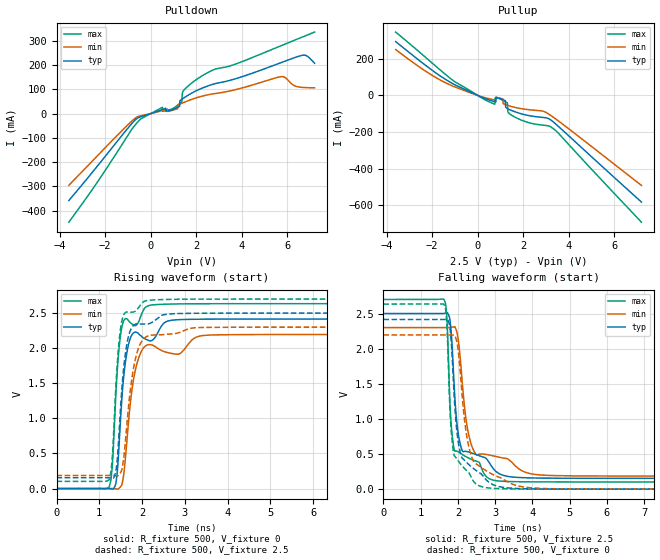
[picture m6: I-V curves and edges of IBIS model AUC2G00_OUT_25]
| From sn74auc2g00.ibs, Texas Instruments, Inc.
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[Model]   AUC2G00_OUT_25
Model_type  Output
Vref =   0
Rref =   500
Cref =   30p
Vmeas =   1.25
| variable   typ   min   max
C_comp   7.45pF   0.27pF   23.62pF
| C_pullup   8.36pF   0.27pF   23.62pF
| C_pulldown   6.53pF   1.89pF   15.75pF
[Temperature Range]   40   100   -40
| Ambient temperature   25   85   -40
[Voltage range]   2.5   2.3   2.7
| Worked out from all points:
|   slope of the pulldown table from 0 to 0.375 V, typ, clamps not added: 30.9 ohm
|   slope of the pullup table from 0 to 0.375 V, typ, clamps not added: 19.2 ohm
|   rising waveform, R_fixture 500, V_fixture 0: 20-80 % time 195ps typ, 258ps min, 157ps max; typ from 0 V to 2.42 V
|   falling waveform, R_fixture 500, V_fixture 2.5: 20-80 % time 226ps typ, 316ps min, 156ps max; typ from 2.5 V to 0.154 V
|   rising waveform, R_fixture 500, V_fixture 2.5: 20-80 % time 192ps typ, 257ps min, 155ps max; typ from 0.154 V to 2.5 V
|   falling waveform, R_fixture 500, V_fixture 0: 20-80 % time 241ps typ, 337ps min, 159ps max; typ from 2.42 V to 0 V
[Pulldown]
| AUC2G00_OUT_25
|   Voltage   I(typ)   I(min)   I(max)
-3.6V     -357.9mA   -295mA     -446.9mA
-445mV    -13.39mA   -9.086mA   -23.04mA
515mV     17.02mA    12.57mA    25.99mA
1.03V     19.04mA    15.49mA    23.85mA
1.27V     29.99mA    38.36mA    41.3mA
1.37V     59.29mA    42.41mA    48.87mA
1.395V    60.81mA    43.42mA    85.06mA
1.48V     65.92mA    46.77mA    98.72mA
2.545V    114.8mA    77.91mA    170.6mA
5.695V    208.4mA    151.5mA    277.8mA
6.74V     240.4mA    107.1mA    317.8mA
7.2V      207mA      105.9mA    335.2mA
[Pullup]
| AUC2G00_OUT_25
|   Voltage   I(typ)   I(min)   I(max)
-3.6V     293.6mA    250.5mA    345.5mA
-960mV    55.5mA     44.14mA    71.53mA
730mV     -33.82mA   -24.42mA   -47.21mA
760mV     -34.84mA   -25.13mA   -47.16mA
770mV     -35.18mA   -25.36mA   -13.07mA
1.115V    -23.84mA   -20.26mA   -27.67mA
1.215V    -28.81mA   -50.48mA   -34.67mA
1.295V    -71.05mA   -53.78mA   -40.2mA
1.345V    -74.3mA    -55.73mA   -93.3mA
1.755V    -94.43mA   -68.81mA   -126mA
3.31V     -143.6mA   -118mA     -180.4mA
7.2V      -582.7mA   -491.8mA   -692.5mA
[Ramp]
| AUC2G00_OUT_25
| variable   typ   min   max
dV/dt_r   1.45/1.97E-10   1.32/2.59E-10   1.58/1.58E-10
dV/dt_f   1.41/2.27E-10   1.28/3.18E-10   1.56/1.58E-10
R_load = 500
[Rising Waveform]
| AUC2G00_OUT_25
R_fixture =   500
C_fixture =   0
L_fixture =   0
V_fixture =   0
V_fixture_min = 0
V_fixture_max = 0
|   Time   V(typ)   V(min)   V(max)
0s        9.791nV    28.67nV    1.858nV
1.23ns    -1.161mV   381.6uV    19.94mV
1.305ns   -6.43mV    211.1uV    333.5mV
1.395ns   105.1mV    -4.992mV   1.436V
1.53ns    1.304V     60.53mV    2.309V
1.66ns    1.987V     788.2mV    2.409V
1.825ns   2.227V     1.637V     2.321V
2.18ns    2.104V     2.051V     2.611V
2.975ns   2.409V     1.973V     2.632V
21.47ns   2.416V     2.195V     2.634V
[Falling Waveform]
| AUC2G00_OUT_25
R_fixture =   500
C_fixture =   0
L_fixture =   0
V_fixture =   2.5
V_fixture_min = 2.3
V_fixture_max = 2.7
|   Time   V(typ)   V(min)   V(max)
0s        2.5V       2.3V       2.7V
1.625ns   2.501V     2.3V       2.702V
1.705ns   2.509V     2.3V       2.428V
1.785ns   2.416V     2.302V     1.261V
1.905ns   1.433V     2.312V     557.2mV
2.075ns   618.4mV    1.796V     509.1mV
2.35ns    519.1mV    652.4mV    427.7mV
2.96ns    285.8mV    472.4mV    127mV
4.555ns   156.2mV    193.6mV    103.1mV
21.47ns   154.5mV    186.3mV    102.6mV
[Rising Waveform]
| AUC2G00_OUT_25
R_fixture =   500
C_fixture =   0
L_fixture =   0
V_fixture =   2.5
V_fixture_min = 2.3
V_fixture_max = 2.7
|   Time   V(typ)   V(min)   V(max)
0s        154.5mV    186.3mV    102.6mV
1.23ns    153.4mV    186.5mV    124.4mV
1.305ns   149.8mV    186.4mV    457.5mV
1.39ns    257.5mV    182.6mV    1.484V
1.525ns   1.406V     260.8mV    2.381V
1.65ns    2.076V     949mV      2.515V
1.8ns     2.326V     1.715V     2.515V
2.09ns    2.345V     2.159V     2.676V
3.11ns    2.497V     2.28V      2.699V
21.47ns   2.5V       2.3V       2.7V
[Falling Waveform]
| AUC2G00_OUT_25
R_fixture =   500
C_fixture =   0
L_fixture =   0
V_fixture =   0
V_fixture_min = 0
V_fixture_max = 0
|   Time   V(typ)   V(min)   V(max)
0s        2.416V     2.195V     2.634V
1.62ns    2.415V     2.195V     2.636V
1.705ns   2.418V     2.195V     2.331V
1.78ns    2.33V      2.195V     1.221V
1.89ns    1.433V     2.192V     501.9mV
2.085ns   477.9mV    1.527V     349.7mV
2.315ns   340.1mV    555.7mV    215.9mV
2.68ns    184.5mV    290mV      29.04mV
4.4ns     1.891mV    7.872mV    502.9uV
21.47ns   20.93uV    2.802uV    10.34uV
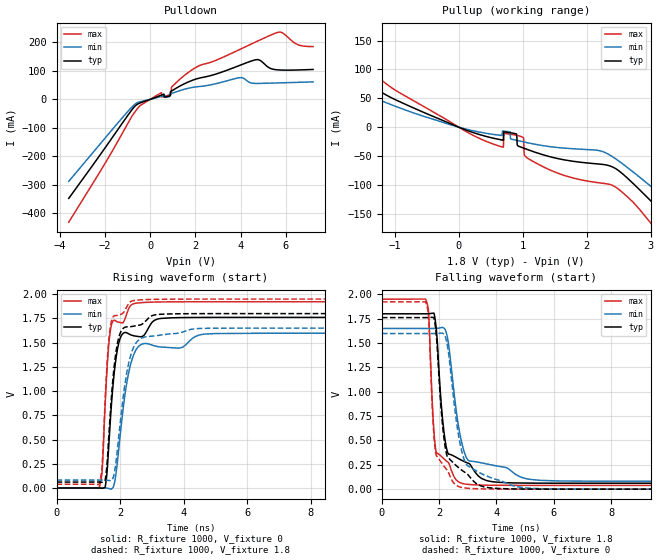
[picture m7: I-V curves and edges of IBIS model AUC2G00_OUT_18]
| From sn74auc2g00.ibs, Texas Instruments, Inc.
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[Model]   AUC2G00_OUT_18
Model_type  Output
Vref =   0
Rref =   1000
Cref =   30p
Vmeas =   0.9
| variable   typ   min   max
C_comp   6.69pF   0.25pF   21.38pF
| C_pullup   7.14pF   1.04pF   21.38pF
| C_pulldown   6.24pF   0.25pF   15.43pF
[Temperature Range]   40   100   -40
| Ambient temperature   25   85   -40
[Voltage range]   1.8   1.65   1.95
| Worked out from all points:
|   slope of the pulldown table from 0 to 0.27 V, typ, clamps not added: 34.4 ohm
|   slope of the pullup table from 0 to 0.27 V, typ, clamps not added: 24.7 ohm
|   rising waveform, R_fixture 1000, V_fixture 0: 20-80 % time 277ps typ, 401ps min, 193ps max; typ from 0 V to 1.76 V
|   falling waveform, R_fixture 1000, V_fixture 1.8: 20-80 % time 318ps typ, 471ps min, 204ps max; typ from 1.8 V to 0.061 V
|   rising waveform, R_fixture 1000, V_fixture 1.8: 20-80 % time 273ps typ, 392ps min, 191ps max; typ from 0.061 V to 1.8 V
|   falling waveform, R_fixture 1000, V_fixture 0: 20-80 % time 324ps typ, 480ps min, 204ps max; typ from 1.76 V to 0 V
[Pulldown]
| AUC2G00_OUT_18
|   Voltage   I(typ)   I(min)   I(max)
-3.6V     -347.6mA   -287.8mA   -431.2mA
-830mV    -38.94mA   -28.94mA   -62.22mA
-405mV    -11.33mA   -7.446mA   -19.55mA
495mV     14.95mA    10.62mA    23.51mA
885mV     12.26mA    19.06mA    15.87mA
925mV     28.54mA    20.16mA    16.88mA
960mV     30.1mA     21.15mA    44.31mA
2.045V    71.87mA    43.99mA    113.3mA
3.92V     118.2mA    75.85mA    173.7mA
4.625V    138.4mA    55.98mA    200.1mA
5.58V     103.9mA    57.6mA     233.8mA
7.2V      105mA      61.31mA    185.3mA
[Pullup]
| AUC2G00_OUT_18
|   Voltage   I(typ)   I(min)   I(max)
-3.6V     267.6mA    221.5mA    318.7mA
-2.61V    174.3mA    138.3mA    219.8mA
-2.13V    131.5mA    101.8mA    171.7mA
110mV     -4.812mA   -3.244mA   -7.318mA
695mV     -22.64mA   -6.826mA   -34.84mA
705mV     -8.168mA   -6.941mA   -10.57mA
980mV     -34.9mA    -24.66mA   -16.5mA
1.11V     -40.21mA   -27.81mA   -56.13mA
2.25V     -64.62mA   -42.31mA   -97.29mA
3.1V      -138.6mA   -111.4mA   -179.7mA
3.915V    -230.4mA   -188mA     -289.7mA
7.2V      -598mA     -503.3mA   -721.1mA
[Ramp]
| AUC2G00_OUT_18
| variable   typ   min   max
dV/dt_r   1.06/2.79E-10   0.97/4.03E-10   1.16/1.93E-10
dV/dt_f   1.05/3.20E-10   0.95/4.76E-10   1.15/2.09E-10
R_load = 1000
[Rising Waveform]
| AUC2G00_OUT_18
R_fixture =   1000
C_fixture =   0
L_fixture =   0
V_fixture =   0
V_fixture_min = 0
V_fixture_max = 0
|   Time   V(typ)   V(min)   V(max)
0s        7.669nV    26.14nV    1.117nV
1.335ns   413.6uV    370.9uV    -1.662mV
1.43ns    -3.344mV   625.4uV    146.9mV
1.545ns   37.2mV     269.6uV    961.4mV
1.71ns    775mV      -11.33mV   1.654V
1.985ns   1.527V     485.5mV    1.709V
2.21ns    1.602V     1.083V     1.797V
2.455ns   1.569V     1.396V     1.904V
3.62ns    1.757V     1.448V     1.921V
22.04ns   1.761V     1.597V     1.922V
[Falling Waveform]
| AUC2G00_OUT_18
R_fixture =   1000
C_fixture =   0
L_fixture =   0
V_fixture =   1.8
V_fixture_min = 1.65
V_fixture_max = 1.95
|   Time   V(typ)   V(min)   V(max)
0s        1.8V       1.65V      1.95V
1.54ns    1.8V       1.65V      1.943V
1.625ns   1.8V       1.65V      1.839V
1.78ns    1.806V     1.65V      775.4mV
1.89ns    1.671V     1.65V      389.8mV
2.085ns   831.3mV    1.659V     334mV
2.245ns   437mV      1.611V     291.3mV
2.81ns    292.7mV    450mV      58.65mV
5.5ns     61.77mV    90.98mV    38.82mV
22.04ns   61.07mV    81.21mV    38.69mV
[Rising Waveform]
| AUC2G00_OUT_18
R_fixture =   1000
C_fixture =   0
L_fixture =   0
V_fixture =   1.8
V_fixture_min = 1.65
V_fixture_max = 1.95
|   Time   V(typ)   V(min)   V(max)
0s        61.05mV    81.2mV     38.68mV
1.335ns   61.41mV    81.51mV    37.46mV
1.43ns    58.04mV    81.7mV     195.3mV
1.535ns   89.78mV    81.57mV    938.5mV
1.705ns   835mV      75.54mV    1.685V
1.96ns    1.555V     537.1mV    1.786V
2.18ns    1.661V     1.129V     1.851V
2.4ns     1.669V     1.432V     1.932V
4.525ns   1.8V       1.647V     1.95V
22.04ns   1.8V       1.65V      1.95V
[Falling Waveform]
| AUC2G00_OUT_18
R_fixture =   1000
C_fixture =   0
L_fixture =   0
V_fixture =   0
V_fixture_min = 0
V_fixture_max = 0
|   Time   V(typ)   V(min)   V(max)
0s        1.761V     1.597V     1.922V
1.535ns   1.761V     1.597V     1.917V
1.625ns   1.761V     1.597V     1.803V
1.775ns   1.763V     1.597V     759.5mV
1.88ns    1.64V      1.597V     368.5mV
2.225ns   408.1mV    1.558V     214.4mV
2.72ns    210.8mV    483.2mV    22.79mV
2.99ns    153.2mV    242.4mV    9.503mV
5.045ns   1.135mV    12.32mV    204.5uV
22.04ns   24.49uV    3.295uV    10.71uV
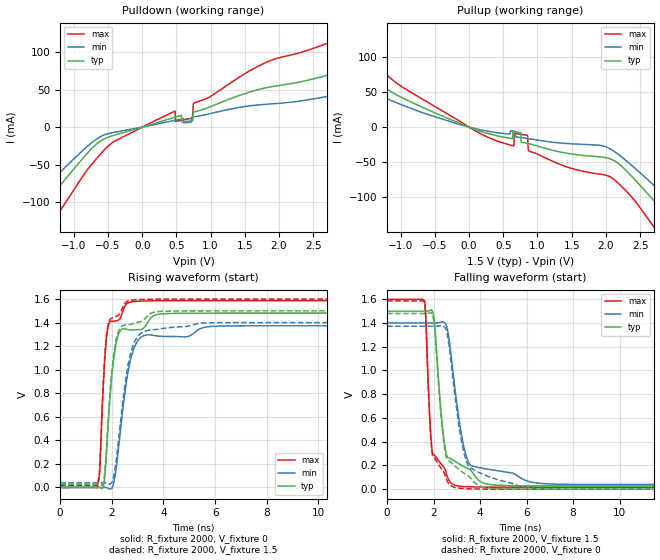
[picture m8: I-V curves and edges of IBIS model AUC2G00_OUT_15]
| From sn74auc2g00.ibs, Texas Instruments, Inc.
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[Model]   AUC2G00_OUT_15
Model_type  Output
Vref =   0
Rref =   2000
Cref =   15p
Vmeas =   0.75
| variable   typ   min   max
C_comp   6.42pF   1.69pF   19.05pF
| C_pullup   6.13pF   1.69pF   19.05pF
| C_pulldown   6.70pF   3.60pF   15.20pF
[Temperature Range]   40   100   -40
| Ambient temperature   25   85   -40
[Voltage range]   1.5   1.4   1.6
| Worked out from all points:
|   slope of the pulldown table from 0 to 0.225 V, typ, clamps not added: 36.6 ohm
|   slope of the pullup table from 0 to 0.225 V, typ, clamps not added: 29.5 ohm
|   rising waveform, R_fixture 2000, V_fixture 0: 20-80 % time 342ps typ, 509ps min, 226ps max; typ from 0 V to 1.48 V
|   falling waveform, R_fixture 2000, V_fixture 1.5: 20-80 % time 406ps typ, 605ps min, 235ps max; typ from 1.5 V to 0.027 V
|   rising waveform, R_fixture 2000, V_fixture 1.5: 20-80 % time 336ps typ, 502ps min, 224ps max; typ from 0.027 V to 1.5 V
|   falling waveform, R_fixture 2000, V_fixture 0: 20-80 % time 408ps typ, 612ps min, 234ps max; typ from 1.48 V to 0 V
[Pulldown]
| AUC2G00_OUT_15
|   Voltage   I(typ)   I(min)   I(max)
-3.6V     -343mA     -284.8mA   -423.7mA
-2.105V   -179.1mA   -144.1mA   -232.4mA
-1.795V   -144.7mA   -115.1mA   -192.1mA
-1.395V   -99.88mA   -78mA      -138.7mA
-395mV    -10.45mA   -6.753mA   -18.28mA
480mV     13.33mA    9.224mA    21.44mA
485mV     13.46mA    9.315mA    7.619mA
735mV     8.724mA    13.39mA    12.06mA
755mV     20.22mA    13.69mA    32.02mA
1.69V     50.03mA    29.61mA    81.13mA
3.34V     86.07mA    49.98mA    134.3mA
7.2V      80.6mA     45.5mA     141.2mA
[Pullup]
| AUC2G00_OUT_15
|   Voltage   I(typ)   I(min)   I(max)
-3.6V     254.2mA    195.1mA    304.8mA
-2.875V   187.5mA    148mA      233.8mA
-2.45V    149.7mA    116.2mA    192.1mA
-1.91V    104.4mA    79.22mA    139.6mA
100mV     -3.652mA   -2.395mA   -5.808mA
650mV     -6.722mA   -5.654mA   -26.6mA
855mV     -23.22mA   -16.17mA   -11.7mA
885mV     -23.88mA   -16.62mA   -34.51mA
2.105V    -46.97mA   -33.55mA   -73.62mA
2.76V     -111.3mA   -88.18mA   -150.1mA
3.36V     -178.2mA   -143.6mA   -230.9mA
7.2V      -605.9mA   -510.3mA   -734mA
[Ramp]
| AUC2G00_OUT_15
| variable   typ   min   max
dV/dt_r   0.89/3.44E-10   0.83/5.15E-10   0.95/2.27E-10
dV/dt_f   0.89/4.07E-10   0.82/6.08E-10   0.95/2.44E-10
R_load = 2000
[Rising Waveform]
| AUC2G00_OUT_15
R_fixture =   2000
C_fixture =   0
L_fixture =   0
V_fixture =   0
V_fixture_min = 0
V_fixture_max = 0
|   Time   V(typ)   V(min)   V(max)
0s        7.042nV    26.32nV    876.9pV
1.43ns    519.8uV    333.3uV    -3.88mV
1.53ns    -1.276mV   511.6uV    132.3mV
1.695ns   28.68mV    721.1uV    966.6mV
1.84ns    460.8mV    -4.356mV   1.347V
2.175ns   1.231V     172.7mV    1.416V
2.675ns   1.339V     1.035V     1.571V
3.21ns    1.349V     1.286V     1.583V
5.81ns    1.48V      1.367V     1.587V
22.06ns   1.481V     1.373V     1.587V
[Falling Waveform]
| AUC2G00_OUT_15
R_fixture =   2000
C_fixture =   0
L_fixture =   0
V_fixture =   1.5
V_fixture_min = 1.4
V_fixture_max = 1.6
|   Time   V(typ)   V(min)   V(max)
0s        1.5V       1.4V       1.6V
1.625ns   1.5V       1.4V       1.583V
1.83ns    1.505V     1.4V       636.4mV
1.95ns    1.498V     1.4V       311.2mV
2.485ns   365mV      1.402V     171.2mV
2.915ns   235.7mV    857.7mV    33.55mV
3.255ns   195.9mV    401mV      22.76mV
3.57ns    165.7mV    206.2mV    19.58mV
6.205ns   27.73mV    59.5mV     16.5mV
22.06ns   27.2mV     38.79mV    16.41mV
[Rising Waveform]
| AUC2G00_OUT_15
R_fixture =   2000
C_fixture =   0
L_fixture =   0
V_fixture =   1.5
V_fixture_min = 1.4
V_fixture_max = 1.6
|   Time   V(typ)   V(min)   V(max)
0s        27.17mV    38.78mV    16.4mV
1.43ns    27.65mV    39.07mV    12.68mV
1.53ns    25.96mV    39.22mV    155.6mV
1.69ns    59.47mV    39.35mV    973.6mV
1.83ns    471.3mV    35.63mV    1.354V
2.15ns    1.236V     198.6mV    1.451V
2.625ns   1.381V     1.036V     1.584V
3.195ns   1.417V     1.318V     1.597V
5.47ns    1.5V       1.396V     1.6V
22.06ns   1.5V       1.4V       1.6V
[Falling Waveform]
| AUC2G00_OUT_15
R_fixture =   2000
C_fixture =   0
L_fixture =   0
V_fixture =   0
V_fixture_min = 0
V_fixture_max = 0
|   Time   V(typ)   V(min)   V(max)
0s        1.481V     1.373V     1.587V
1.625ns   1.48V      1.373V     1.568V
1.83ns    1.485V     1.373V     610.9mV
1.945ns   1.477V     1.372V     299.2mV
2.465ns   357.5mV    1.37V      132.7mV
2.865ns   204.4mV    879.6mV    17.26mV
3.205ns   148.9mV    402.3mV    6.494mV
3.51ns    109.5mV    193.3mV    3.32mV
5.785ns   771.2uV    21.4mV     120.3uV
22.06ns   29.25uV    5.444uV    11.79uV
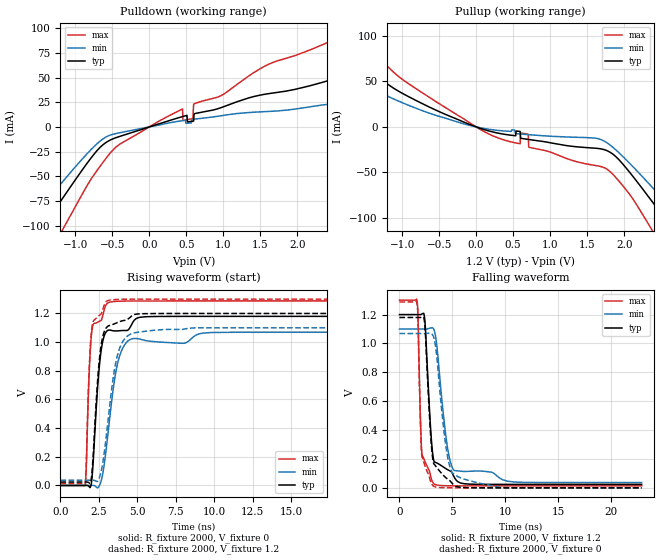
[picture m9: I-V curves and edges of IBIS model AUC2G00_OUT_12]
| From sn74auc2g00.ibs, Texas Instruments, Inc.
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[Model]   AUC2G00_OUT_12
Model_type  Output
Vref =   0
Rref =   2000
Cref =   15p
Vmeas =   0.6
| variable   typ   min   max
C_comp   5.93pF   2.37pF   15.74pF
| C_pullup   5.52pF   2.37pF   15.74pF
| C_pulldown   6.35pF   4.16pF   14.94pF
[Temperature Range]   40   100   -40
| Ambient temperature   25   85   -40
[Voltage range]   1.2   1.1   1.3
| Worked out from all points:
|   slope of the pulldown table from 0 to 0.18 V, typ, clamps not added: 42.3 ohm
|   slope of the pullup table from 0 to 0.18 V, typ, clamps not added: 38.7 ohm
|   rising waveform, R_fixture 2000, V_fixture 0: 20-80 % time 482ps typ, 795ps min, 284ps max; typ from 0 V to 1.18 V
|   falling waveform, R_fixture 2000, V_fixture 1.2: 20-80 % time 560ps typ, 947ps min, 290ps max; typ from 1.2 V to 0.024 V
|   rising waveform, R_fixture 2000, V_fixture 1.2: 20-80 % time 474ps typ, 785ps min, 278ps max; typ from 0.024 V to 1.2 V
|   falling waveform, R_fixture 2000, V_fixture 0: 20-80 % time 558ps typ, 955ps min, 287ps max; typ from 1.18 V to 0 V
[Pulldown]
| AUC2G00_OUT_12
|   Voltage   I(typ)   I(min)   I(max)
-3.6V     -338.3mA   -281.2mA   -417.3mA
-1.81V    -142.4mA   -113.5mA   -188.2mA
-1.485V   -106.7mA   -83.68mA   -145.8mA
-1.225V   -78.14mA   -60.24mA   -111.4mA
-715mV    -24.74mA   -17.64mA   -45.05mA
-390mV    -9.376mA   -5.759mA   -17.06mA
450mV     10.5mA     6.398mA    18.24mA
590mV     5.848mA    7.731mA    8.546mA
605mV     12.96mA    7.861mA    23.36mA
2.86V     55.94mA    19.09mA    100.7mA
3.425V    44.57mA    20.08mA    119.3mA
7.2V      57.06mA    26.82mA    108mA
[Pullup]
| AUC2G00_OUT_12
|   Voltage   I(typ)   I(min)   I(max)
-3.6V     224.6mA    100.8mA    291.5mA
-2.7V     158.6mA    66.17mA    205.2mA
-2.11V    110.3mA    77.88mA    148.7mA
-1.68V    77.88mA    55.75mA    108.7mA
-1.025V   38.18mA    27.56mA    53.97mA
50mV      -1.427mA   -842.9uA   -2.489mA
700mV     -13.68mA   -8.451mA   -7.891mA
1.78V     -26.5mA    -18.1mA    -47.09mA
2.4V      -84.34mA   -68.12mA   -116.4mA
2.695V    -116.7mA   -94.74mA   -156.1mA
3.045V    -155.5mA   -127mA     -202.8mA
7.2V      -615.6mA   -521.5mA   -745mA
[Ramp]
| AUC2G00_OUT_12
| variable   typ   min   max
dV/dt_r   0.72/4.91E-10   0.65/8.04E-10   0.77/2.86E-10
dV/dt_f   0.71/5.65E-10   0.64/9.53E-10   0.78/2.98E-10
R_load = 2000
[Rising Waveform]
| AUC2G00_OUT_12
R_fixture =   2000
C_fixture =   0
L_fixture =   0
V_fixture =   0
V_fixture_min = 0
V_fixture_max = 0
|   Time   V(typ)   V(min)   V(max)
0s        6.587nV    27.93nV    705.3pV
1.625ns   446.8uV    213.2uV    3.711mV
1.84ns    -4.255mV   499.1uV    700.9mV
1.97ns    -4.138mV   747.2uV    989.2mV
2.135ns   171.6mV    701uV      1.123V
2.58ns    882.7mV    10.28mV    1.148V
3.11ns    1.084V     377.6mV    1.275V
3.75ns    1.079V     865.8mV    1.285V
4.615ns   1.119V     1.022V     1.287V
22.92ns   1.18V      1.069V     1.287V
[Falling Waveform]
| AUC2G00_OUT_12
R_fixture =   2000
C_fixture =   0
L_fixture =   0
V_fixture =   1.2
V_fixture_min = 1.1
V_fixture_max = 1.3
|   Time   V(typ)   V(min)   V(max)
0s        1.2V       1.1V       1.3V
1.66ns    1.2V       1.1V       1.295V
1.75ns    1.2V       1.1V       1.198V
2.07ns    1.202V     1.1V       303.3mV
2.32ns    1.204V     1.099V     200.4mV
2.985ns   373.3mV    1.107V     70.99mV
3.29ns    181.2mV    1.092V     26.82mV
4.48ns    129.2mV    312.9mV    14.7mV
5.17ns    76.42mV    121.3mV    14.16mV
22.92ns   24.01mV    36.66mV    13.87mV
[Rising Waveform]
| AUC2G00_OUT_12
R_fixture =   2000
C_fixture =   0
L_fixture =   0
V_fixture =   1.2
V_fixture_min = 1.1
V_fixture_max = 1.3
|   Time   V(typ)   V(min)   V(max)
0s        23.98mV    36.64mV    13.86mV
1.625ns   24.35mV    36.82mV    21.51mV
1.835ns   20.76mV    37mV       714.5mV
1.955ns   22.5mV     37.12mV    990.3mV
2.115ns   184.9mV    37.15mV    1.139V
2.55ns    894.1mV    60.87mV    1.188V
3.03ns    1.106V     388.9mV    1.287V
3.705ns   1.136V     906.6mV    1.298V
4.68ns    1.186V     1.061V     1.3V
22.92ns   1.2V       1.1V       1.3V
[Falling Waveform]
| AUC2G00_OUT_12
R_fixture =   2000
C_fixture =   0
L_fixture =   0
V_fixture =   0
V_fixture_min = 0
V_fixture_max = 0
|   Time   V(typ)   V(min)   V(max)
0s        1.18V      1.069V     1.287V
1.655ns   1.18V      1.069V     1.282V
1.75ns    1.18V      1.069V     1.177V
2.06ns    1.181V     1.069V     295.7mV
2.31ns    1.179V     1.069V     178mV
2.945ns   373.5mV    1.069V     45.97mV
3.205ns   178.4mV    1.05V      13.46mV
4.42ns    68.74mV    276.4mV    819.4uV
5.105ns   22.67mV    97.94mV    293.4uV
22.92ns   32.57uV    9.226uV    12.49uV
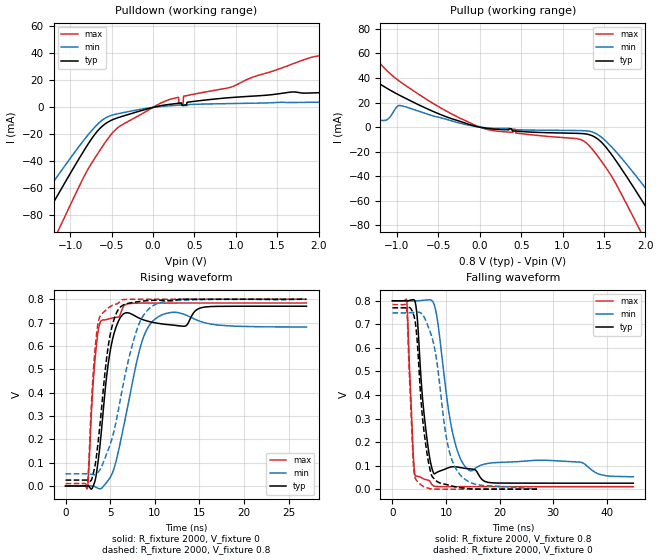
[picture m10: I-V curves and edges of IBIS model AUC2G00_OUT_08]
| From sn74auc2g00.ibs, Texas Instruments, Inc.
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[Model]   AUC2G00_OUT_08
Model_type  Output
Vref =   0
Rref =   2000
Cref =   15p
Vmeas =   0.4
| variable   typ   min   max
C_comp   5.67pF   2.72pF   7.64pF
| C_pullup   5.14pF   2.72pF   7.64pF
| C_pulldown   6.20pF   5.44pF   6.81pF
[Temperature Range]   40   100   -40
| Ambient temperature   25   85   -40
[Voltage range]   0.8   0.8   0.8
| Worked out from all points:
|   slope of the pulldown table from 0 to 0.12 V, typ, clamps not added: 77.1 ohm
|   slope of the pullup table from 0 to 0.12 V, typ, clamps not added: 92.8 ohm
|   rising waveform, R_fixture 2000, V_fixture 0: 20-80 % time 1.39ns typ, 2.21ns min, 814ps max; typ from 0 V to 0.77 V
|   falling waveform, R_fixture 2000, V_fixture 0.8: 20-80 % time 1.76ns typ, 2.84ns min, 866ps max; typ from 0.8 V to 0.026 V
|   rising waveform, R_fixture 2000, V_fixture 0.8: 20-80 % time 1.37ns typ, 2.64ns min, 761ps max; typ from 0.025 V to 0.8 V
|   falling waveform, R_fixture 2000, V_fixture 0: 20-80 % time 1.78ns typ, 2.87ns min, 865ps max; typ from 0.77 V to 0 V
[Pulldown]
| AUC2G00_OUT_08
|   Voltage   I(typ)   I(min)   I(max)
-3.6V     -332mA     -277.5mA   -406.5mA
-1.635V   -117.5mA   -94.15mA   -155.2mA
-1.375V   -89.26mA   -70.66mA   -121.5mA
-1.155V   -65.6mA    -51.21mA   -92.88mA
-630mV    -14.96mA   -10.34mA   -30.86mA
-430mV    -7.788mA   -4.786mA   -15.33mA
-90mV     -1.494mA   -794.3uA   -3.292mA
210mV     2.329mA    1.254mA    6.027mA
365mV     1.692mA    1.285mA    2.781mA
1.98V     10.83mA    3.867mA    38.03mA
2.365V    11.74mA    4.199mA    33.49mA
7.2V      23.85mA    8.894mA    59.33mA
[Pullup]
| AUC2G00_OUT_08
|   Voltage   I(typ)   I(min)   I(max)
-3.6V     79.74mA    9.11mA     185.5mA
-3.08V    78.24mA    9.441mA    162.7mA
-1.59V    27.55mA    11.02mA    82.8mA
-1.305V   38.33mA    6.645mA    59.6mA
-1.13V    31.97mA    5.759mA    46.58mA
-975mV    26.17mA    17.62mA    37.64mA
-245mV    4.854mA    3.296mA    7.479mA
1.36V     -7.061mA   -3.966mA   -18.08mA
1.875V    -50.9mA    -38.75mA   -76.11mA
2.115V    -76.5mA    -59.54mA   -107.8mA
2.405V    -108mA     -85.49mA   -146mA
7.2V      -633.7mA   -537.1mA   -765.1mA
[Ramp]
| AUC2G00_OUT_08
| variable   typ   min   max
dV/dt_r   0.47/1.41E-09   0.45/2.50E-09   0.48/8.20E-10
dV/dt_f   0.47/1.76E-09   0.45/2.84E-09   0.48/8.72E-10
R_load = 2000
[Rising Waveform]
| AUC2G00_OUT_08
R_fixture =   2000
C_fixture =   0
L_fixture =   0
V_fixture =   0
V_fixture_min = 0
V_fixture_max = 0
|   Time   V(typ)   V(min)   V(max)
0s        8.079nV    45.62nV    527.9pV
2.445ns   704.3uV    733.6uV    -7.839mV
3.255ns   16.1mV     -2.427mV   521.8mV
3.655ns   108.7mV    -9.825mV   665.4mV
4.025ns   240.2mV    -9.757mV   709.3mV
4.92ns    559.9mV    32.03mV    716.5mV
5.985ns   711mV      160.5mV    724.8mV
8.38ns    716.7mV    595.3mV    783.3mV
10.06ns   698.7mV    716.2mV    783.6mV
27ns      770mV      681mV      783.7mV
[Falling Waveform]
| AUC2G00_OUT_08
R_fixture =   2000
C_fixture =   0
L_fixture =   0
V_fixture =   0.8
V_fixture_min = 0.8
V_fixture_max = 0.8
|   Time   V(typ)   V(min)   V(max)
0s        800mV      800mV      800mV
2.66ns    799.1mV    799.8mV    801.1mV
3.87ns    804.8mV    799.4mV    156.6mV
4.29ns    790.2mV    799.4mV    55.11mV
5.975ns   304.7mV    802.7mV    42.26mV
7.77ns    65.54mV    784.9mV    13.01mV
11.1ns    94.86mV    253.6mV    10.67mV
14.07ns   87.05mV    84.78mV    10.64mV
28.86ns   25.55mV    122.6mV    10.61mV
45ns      25.5mV     52.61mV    10.6mV
[Rising Waveform]
| AUC2G00_OUT_08
R_fixture =   2000
C_fixture =   0
L_fixture =   0
V_fixture =   0.8
V_fixture_min = 0.8
V_fixture_max = 0.8
|   Time   V(typ)   V(min)   V(max)
0s        25.46mV    52.25mV    10.6mV
2.415ns   25.41mV    52.27mV    7.024mV
2.55ns    24.63mV    51.97mV    60.59mV
3.05ns    45.66mV    48.87mV    456.3mV
3.5ns     140.6mV    54.08mV    661.4mV
4.805ns   605mV      158.4mV    763mV
6.1ns     764.9mV    363.1mV    790.2mV
7.91ns    788.2mV    660.6mV    799.7mV
9.54ns    794.6mV    765.5mV    799.8mV
27ns      799.9mV    800.6mV    800mV
[Falling Waveform]
| AUC2G00_OUT_08
R_fixture =   2000
C_fixture =   0
L_fixture =   0
V_fixture =   0
V_fixture_min = 0
V_fixture_max = 0
|   Time   V(typ)   V(min)   V(max)
0s        770mV      748.6mV    783.8mV
2.64ns    769.8mV    748.6mV    770mV
3.88ns    745.2mV    750.3mV    120.2mV
4.54ns    651.4mV    751.7mV    35.78mV
5.77ns    270.3mV    736.3mV    11.76mV
7.485ns   51.94mV    636.7mV    548.9uV
10.19ns   19.15mV    204.1mV    73.34uV
12.29ns   7.903mV    71.23mV    49.52uV
15.86ns   375uV      18.84mV    31.95uV
27ns      59.72uV    2.382mV    15.65uV
